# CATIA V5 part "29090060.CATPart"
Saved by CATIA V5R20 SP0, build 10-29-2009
Part number: 29090060
Definition: NONE
Nomenclature: 29090060
Source: Unknown
Description: 29090060
Bounding box of the stored display mesh (mm): x -30 to 44.548, y -59 to 93.548, z -49 to 49
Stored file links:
  C:\Users\Utente\Desktop\IO LAVORO\3D X SITO CF\X SITO\PLASTICA\RF1\29090060.CATPart

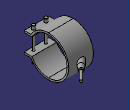
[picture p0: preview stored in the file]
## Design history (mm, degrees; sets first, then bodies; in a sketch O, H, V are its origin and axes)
Body1 "29090060" (main body)
  Solid1: solid without history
